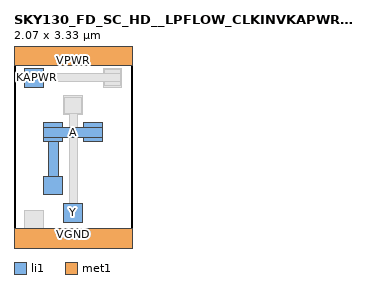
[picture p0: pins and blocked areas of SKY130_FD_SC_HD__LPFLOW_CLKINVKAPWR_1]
MACRO SKY130_FD_SC_HD__LPFLOW_CLKINVKAPWR_1
 CLASS CORE ;
 FOREIGN SKY130_FD_SC_HD__LPFLOW_CLKINVKAPWR_1 0 0 ;
 SIZE 2.07 BY 3.33 ;
 ORIGIN 0 0 ;
 SYMMETRY X Y R90 ;
 SITE unit ;
  PIN VPWR
   DIRECTION INOUT ;
   USE POWER ;
   SHAPE ABUTMENT ;
    PORT
     CLASS CORE ;
       LAYER li1 ;
        RECT 0.00000000 3.09000000 2.07000000 3.57000000 ;
       LAYER met1 ;
        RECT 0.00000000 3.09000000 2.07000000 3.57000000 ;
    END
  END VPWR

  PIN VGND
   DIRECTION INOUT ;
   USE POWER ;
   SHAPE ABUTMENT ;
    PORT
     CLASS CORE ;
       LAYER li1 ;
        RECT 0.00000000 -0.24000000 2.07000000 0.24000000 ;
       LAYER met1 ;
        RECT 0.00000000 -0.24000000 2.07000000 0.24000000 ;
    END
  END VGND

  PIN Y
   DIRECTION INOUT ;
   USE SIGNAL ;
   SHAPE ABUTMENT ;
    PORT
     CLASS CORE ;
       LAYER li1 ;
        RECT 0.87000000 0.35000000 1.20000000 0.68000000 ;
    END
  END Y

  PIN KAPWR
   DIRECTION INOUT ;
   USE SIGNAL ;
   SHAPE ABUTMENT ;
    PORT
     CLASS CORE ;
       LAYER li1 ;
        RECT 0.18000000 2.71500000 0.51000000 3.04500000 ;
    END
  END KAPWR

  PIN A
   DIRECTION INOUT ;
   USE SIGNAL ;
   SHAPE ABUTMENT ;
    PORT
     CLASS CORE ;
       LAYER li1 ;
        RECT 0.52500000 0.82500000 0.85500000 1.15500000 ;
        RECT 0.60500000 1.15500000 0.77500000 1.76000000 ;
        RECT 0.52500000 1.76000000 0.85500000 1.84000000 ;
        RECT 1.21500000 1.76000000 1.54500000 1.84000000 ;
        RECT 0.52500000 1.84000000 1.54500000 2.01000000 ;
        RECT 0.52500000 2.01000000 0.85500000 2.09000000 ;
        RECT 1.21500000 2.01000000 1.54500000 2.09000000 ;
    END
  END A

 OBS
    LAYER polycont ;
     RECT 0.60500000 0.90500000 0.77500000 1.07500000 ;
     RECT 0.60500000 1.84000000 0.77500000 2.01000000 ;
     RECT 1.29500000 1.84000000 1.46500000 2.01000000 ;

    LAYER pdiffc ;
     RECT 0.95000000 2.31000000 1.12000000 2.48000000 ;
     RECT 0.26000000 2.79500000 0.43000000 2.96500000 ;
     RECT 1.64000000 2.79500000 1.81000000 2.96500000 ;

    LAYER ndiffc ;
     RECT 0.26000000 0.30000000 0.43000000 0.47000000 ;
     RECT 0.95000000 0.43000000 1.12000000 0.60000000 ;

    LAYER li1 ;
     RECT 0.00000000 -0.24000000 2.07000000 0.24000000 ;
     RECT 0.18000000 0.24000000 0.51000000 0.55000000 ;
     RECT 0.87000000 0.35000000 1.20000000 0.68000000 ;
     RECT 0.52500000 0.82500000 0.85500000 1.15500000 ;
     RECT 0.60500000 1.15500000 0.77500000 1.76000000 ;
     RECT 0.52500000 1.76000000 0.85500000 1.84000000 ;
     RECT 1.21500000 1.76000000 1.54500000 1.84000000 ;
     RECT 0.52500000 1.84000000 1.54500000 2.01000000 ;
     RECT 0.52500000 2.01000000 0.85500000 2.09000000 ;
     RECT 1.21500000 2.01000000 1.54500000 2.09000000 ;
     RECT 0.87000000 2.23000000 1.20000000 2.56000000 ;
     RECT 0.18000000 2.71500000 0.51000000 3.04500000 ;
     RECT 1.56000000 2.71500000 1.89000000 3.04500000 ;
     RECT 0.00000000 3.09000000 2.07000000 3.57000000 ;

    LAYER viali ;
     RECT 0.26000000 -0.08500000 0.43000000 0.08500000 ;
     RECT 0.95000000 0.43000000 1.12000000 0.60000000 ;
     RECT 0.95000000 2.31000000 1.12000000 2.48000000 ;
     RECT 0.26000000 2.79500000 0.43000000 2.96500000 ;
     RECT 1.64000000 2.79500000 1.81000000 2.96500000 ;
     RECT 0.14500000 3.24500000 0.31500000 3.41500000 ;

    LAYER met1 ;
     RECT 0.00000000 -0.24000000 2.07000000 0.24000000 ;
     RECT 0.89000000 0.37000000 1.18000000 0.66000000 ;
     RECT 0.96500000 0.66000000 1.10500000 2.25000000 ;
     RECT 0.89000000 2.25000000 1.18000000 2.54000000 ;
     RECT 0.20000000 2.73500000 0.49000000 2.81000000 ;
     RECT 1.58000000 2.73500000 1.87000000 2.81000000 ;
     RECT 0.20000000 2.81000000 1.87000000 2.95000000 ;
     RECT 0.20000000 2.95000000 0.49000000 3.02500000 ;
     RECT 1.58000000 2.95000000 1.87000000 3.02500000 ;
     RECT 0.00000000 3.09000000 2.07000000 3.57000000 ;

    LAYER via ;


    LAYER met2 ;


    LAYER via2 ;


    LAYER met3 ;


 END
END SKY130_FD_SC_HD__LPFLOW_CLKINVKAPWR_1
